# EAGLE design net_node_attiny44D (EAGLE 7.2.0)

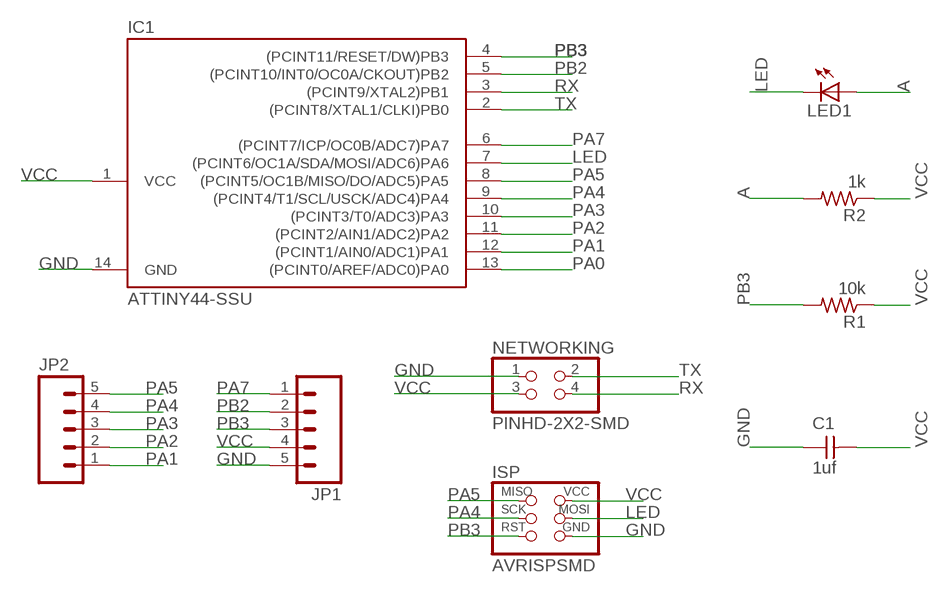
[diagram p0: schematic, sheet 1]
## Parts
C1  1uf  UNPOLARIZED_CAPACITOR1206  [1206]
IC1  ATTINY44-SSU  [SOIC14]
ISP  AVRISPSMD  [2X03SMD]
JP1  M05PTH  [1X05]
JP2  M05PTH  [1X05]
LED1  LED1206  [1206]
NETWORKING  PINHD-2X2-SMD  [2X02SMD]
R1  10k  RESISTOR1206  [1206]
R2  1k  RESISTOR1206  [1206]

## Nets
A: LED1.1(A) R2.2
GND: C1.1 IC1.14(GND) ISP.6(GND) JP1.5 NETWORKING.1
LED: IC1.7((PCINT6/OC1A/SDA/MOSI/ADC6)PA6) ISP.4(MOSI) LED1.2(C)
PA0: IC1.13((PCINT0/AREF/ADC0)PA0)
PA1: IC1.12((PCINT1/AIN0/ADC1)PA1) JP2.1
PA2: IC1.11((PCINT2/AIN1/ADC2)PA2) JP2.2
PA3: IC1.10((PCINT3/T0/ADC3)PA3) JP2.3
PA4: IC1.9((PCINT4/T1/SCL/USCK/ADC4)PA4) ISP.3(SCK) JP2.4
PA5: IC1.8((PCINT5/OC1B/MISO/DO/ADC5)PA5) ISP.1(MISO) JP2.5
PA7: IC1.6((PCINT7/ICP/OC0B/ADC7)PA7) JP1.1
PB2: IC1.5((PCINT10/INT0/OC0A/CKOUT)PB2) JP1.2
PB3: IC1.4((PCINT11/RESET/DW)PB3) ISP.5(RST) JP1.3 R1.2
RX: IC1.3((PCINT9/XTAL2)PB1) NETWORKING.4
TX: IC1.2((PCINT8/XTAL1/CLKI)PB0) NETWORKING.2
VCC: C1.2 IC1.1(VCC) ISP.2(VCC) JP1.4 NETWORKING.3 R1.1 R2.1

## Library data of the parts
C1 = 01_FAB_RHello:UNPOLARIZED_CAPACITOR: unpolarized_capacitor
IC1 = 01_FAB_RHello:ATTINY44
ISP = 01_FAB_RHello:AVRISP
JP1 JP2 = SparkFun-Connectors:M05: Header 5 Standard 5-pin 0.1" header. Use with straight break away headers (SKU : PRT-00116), right angle break away headers (PRT-00553), swiss pins (PRT-00743), machine pins (PRT-00117), and female headers (PRT-00115). Molex polarized connector foot print use with SKU : PRT-08230 with associated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
LED1 = 01_FAB_RHello:LED
NETWORKING = fab:PINHD-2X2-SMD
R1 R2 = 01_FAB_RHello:RESISTOR

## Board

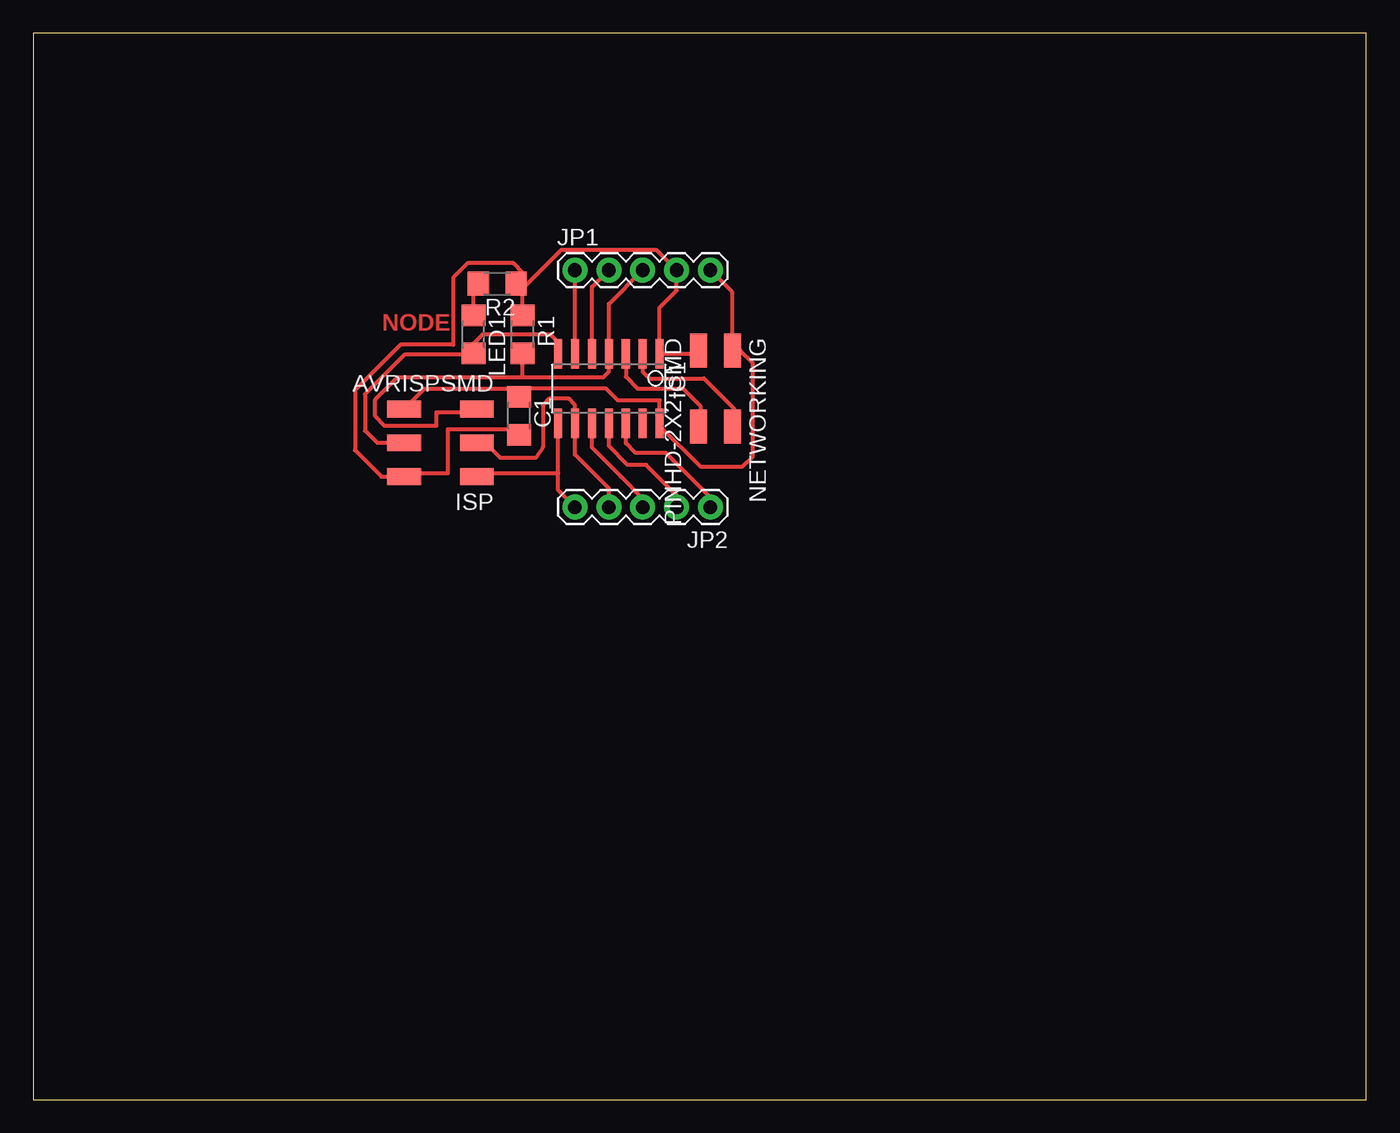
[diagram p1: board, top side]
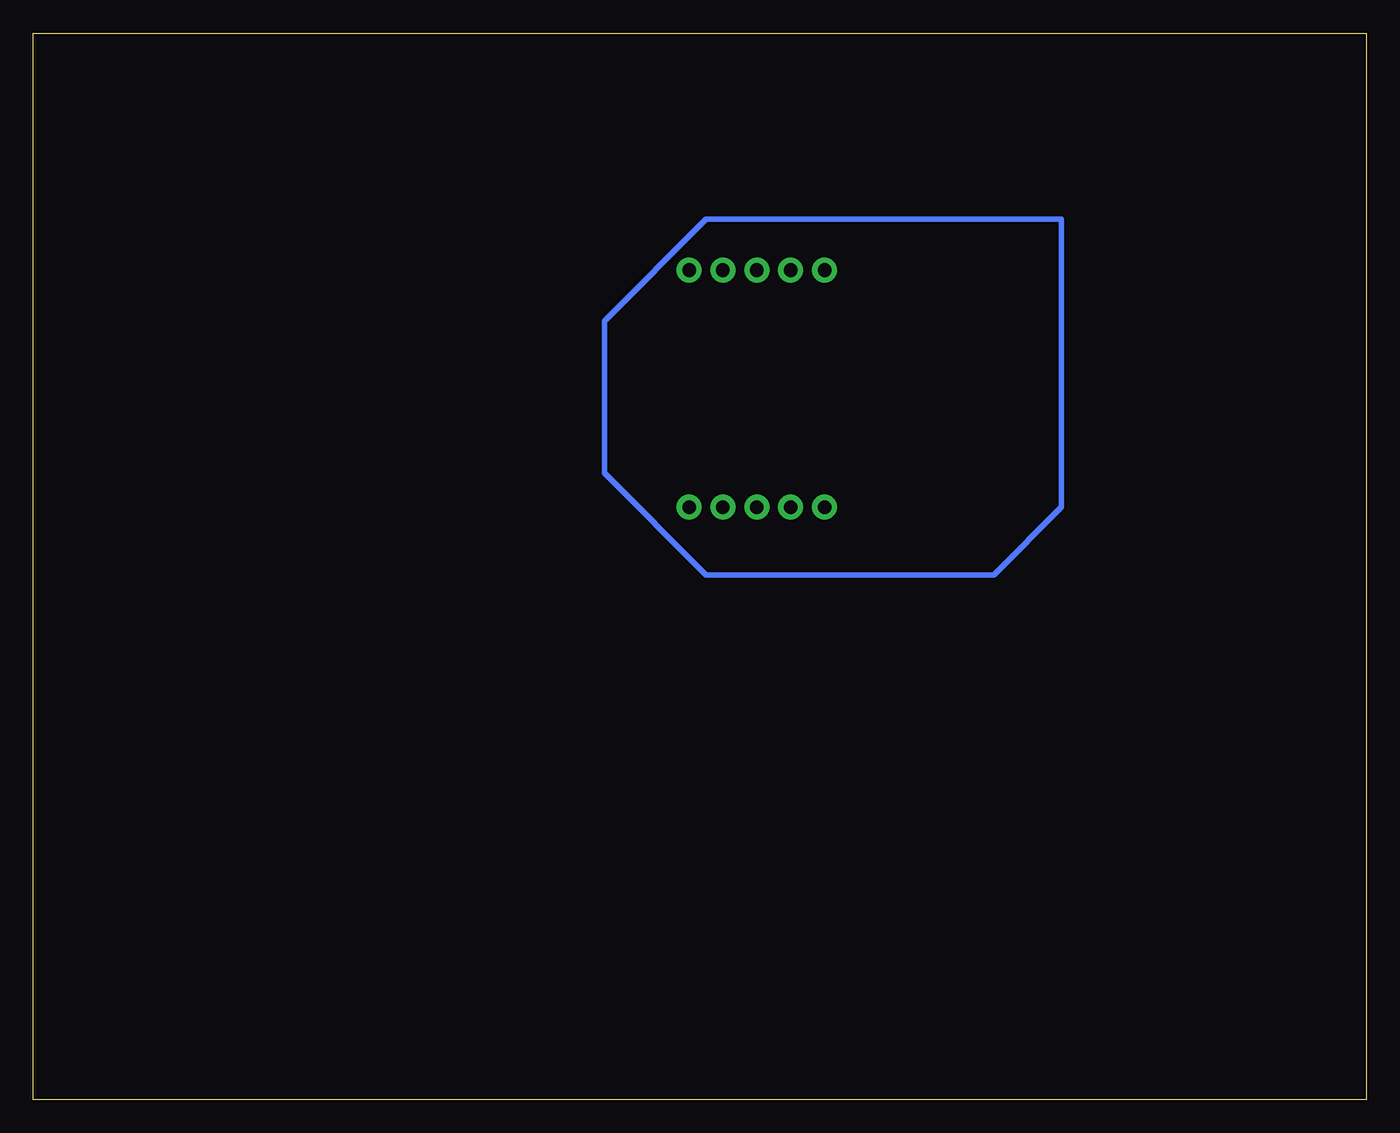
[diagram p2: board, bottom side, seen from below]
Size 100 x 80 mm. Coordinates in mm from the lower left corner, seen from the top.
Outline: 0,0 100,0 100,80 0,80 0,0
Copper layers (1*16): Top 0.035mm / dielectric 1.5mm / Bottom 0.035mm
Design rules "default": minimum track width 10mil, minimum drill 24mil, track to track 8mil, track to pad 8mil, pad to pad 8mil, via to via 8mil, smd to smd 8mil, copper to edge 40mil, drill to drill 8mil, minimum pad ring 10mil, minimum via ring 8mil, stop-mask expansion 4mil, vias tented up to drill 0mil, thermal gap 10mil

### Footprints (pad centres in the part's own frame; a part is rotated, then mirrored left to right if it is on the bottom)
1206 = smd 1.6 x 1.803: 1 -1.422,0; 2 1.422,0
SOIC14 = smd 0.61 x 2.21: 1 -3.81,-2.603; 2 -2.54,-2.603; 3 -1.27,-2.603; 4 0,-2.603; 5 1.27,-2.603; 6 2.54,-2.603; 7 3.81,-2.603; 8 3.81,2.603; 9 2.54,2.603; 10 1.27,2.603; 11 0,2.603; 12 -1.27,2.603; 13 -2.54,2.603; 14 -3.81,2.603
2X03SMD = smd 2.54 x 1.27: 1 -2.54,2.54; 2 2.92,2.54; 3 -2.54,0; 4 2.92,0; 5 -2.54,-2.54; 6 2.92,-2.54
1X05 = drill 1.016 pad 1.88: 1 0,0; 2 2.54,0; 3 5.08,0; 4 7.62,0; 5 10.16,0
2X02SMD = smd 2.54 x 1.27: 1 -2.857,1.27; 2 2.857,1.27; 3 -2.857,-1.27; 4 2.857,-1.27

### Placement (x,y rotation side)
C1  36.45,51.31 270 top
IC1  43.18,53.34 180 top
ISP  30.73,49.28 180 top
JP1  40.64,62.23 0 top
JP2  50.8,44.45 180 top
LED1  33.02,57.4 270 top
NETWORKING  51.18,53.34 270 top
R1  36.7,57.4 270 top
R2  34.8,61.21 180 top

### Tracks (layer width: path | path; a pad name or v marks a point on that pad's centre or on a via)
A
  Top 0.305: LED1.1 33.02,61.21 R2.2
GND
  Top 0.305: 36.83,53.34 42.98,53.34 43.86,52.45 46.99,52.45 IC1.14 46.99,50.55 50.04,47.5 53.21,47.5 53.98,48.26 53.98,55.24 53.02,56.2 NETWORKING.1 52.45,60.58 JP1.5 | 36.45,53.34 C1.1 | 36.45,52.48 C1.1 | ISP.6 29.34,53.34 36.45,53.34 | 36.45,53.34 36.83,53.34 | 36.83,53.34 C1.1
LED
  Top 0.305: 39.31,55.94 39.31,56.89 38.8,57.4 33.7,57.4 33.02,56.72 LED1.2 33.02,55.88 27.85,55.88 24.89,52.92 24.89,50.19 25.81,49.28 ISP.4
  Top 0.406: IC1.7 39.37,56.13 | IC1.7 39.31,55.94 | 39.37,56.64 IC1.7
N$1
  Bottom 0.406: 22.86,66.04 22.86,44.45 27.94,39.37 49.53,39.37 57.15,46.99 57.15,58.42 49.53,66.04 22.86,66.04
PA1
  Top 0.305: JP2.1 50.8,45.18 47.47,48.51 45.19,48.51 44.45,49.26 IC1.12
PA2
  Top 0.305: IC1.11 43.18,50.16 43.18,49.68 43.18,49.05 44.6,47.62 45.97,47.62 48.26,45.34 JP2.2
PA3
  Top 0.305: JP2.3 45.72,45.11 44.09,46.74 41.91,48.92 IC1.10
PA4
  Top 0.305: JP2.4 43.18,45.85 40.64,48.39 IC1.9 40.64,52.12 40.18,52.58 38.69,52.58 38.23,52.12 38.23,48.95 37.67,48.13 35.05,48.13 34.29,48.9 33.66,48.9 ISP.3
PA5
  Top 0.305: JP2.5 39.37,45.72 39.37,46.99 | 39.37,46.99 IC1.8 | ISP.1 33.27,46.99 39.37,46.99
PA7
  Top 0.305: IC1.6 JP1.1
PB2
  Top 0.305: IC1.5 41.91,60.96 JP1.2
PB3
  Top 0.305: JP1.3 43.18,59.69 IC1.4 43.18,54.61 42.77,54.2 36.7,54.2 | 36.7,54.2 R1.2 | ISP.5 33.27,51.56 30.23,51.56 30.23,50.55 26.37,50.55 25.65,51.26 25.65,52.51 27.35,54.2 36.7,54.2
RX
  Top 0.305: IC1.3 44.45,54.24 45.35,53.34 48.73,53.34 50.04,52.03 50.04,50.48 NETWORKING.4
TX
  Top 0.305: IC1.2 45.72,54.61 46.23,54.1 50.32,54.1 52.58,51.84 52.58,50.48 NETWORKING.2
VCC
  Top 0.305: R1.1 36.7,61.21 R2.1 | 36.83,50.55 C1.2 36.32,49.89 36.32,50.29 31.11,50.29 31.11,46.99 27.81,46.99 ISP.2 26.11,46.74 24.13,48.72 24.13,53.23 27.54,56.64 31.5,56.64 31.5,61.66 32.57,62.74 36.02,62.74 36.7,62.05 R1.1 | NETWORKING.3 49.91,55.94 IC1.1 46.99,59.44 48.26,60.71 JP1.4 46.74,63.75 39.62,63.75 36.7,60.83 R1.1 | R1.1 36.7,61.59

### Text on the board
Top: NODE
